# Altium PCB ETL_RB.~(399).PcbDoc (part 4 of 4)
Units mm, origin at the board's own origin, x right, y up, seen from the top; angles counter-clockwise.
Board outline 130.3 x 56.5 mm, 8 copper layers (Top Layer, plane 1, M1, plane 2, plane 3, M2, plane 4, Bottom Layer), stack 0.972 mm thick; 211 components, 188 nets, 1930 pads, 1008 vias.
Unrouted connection lines stored in the file: 383.

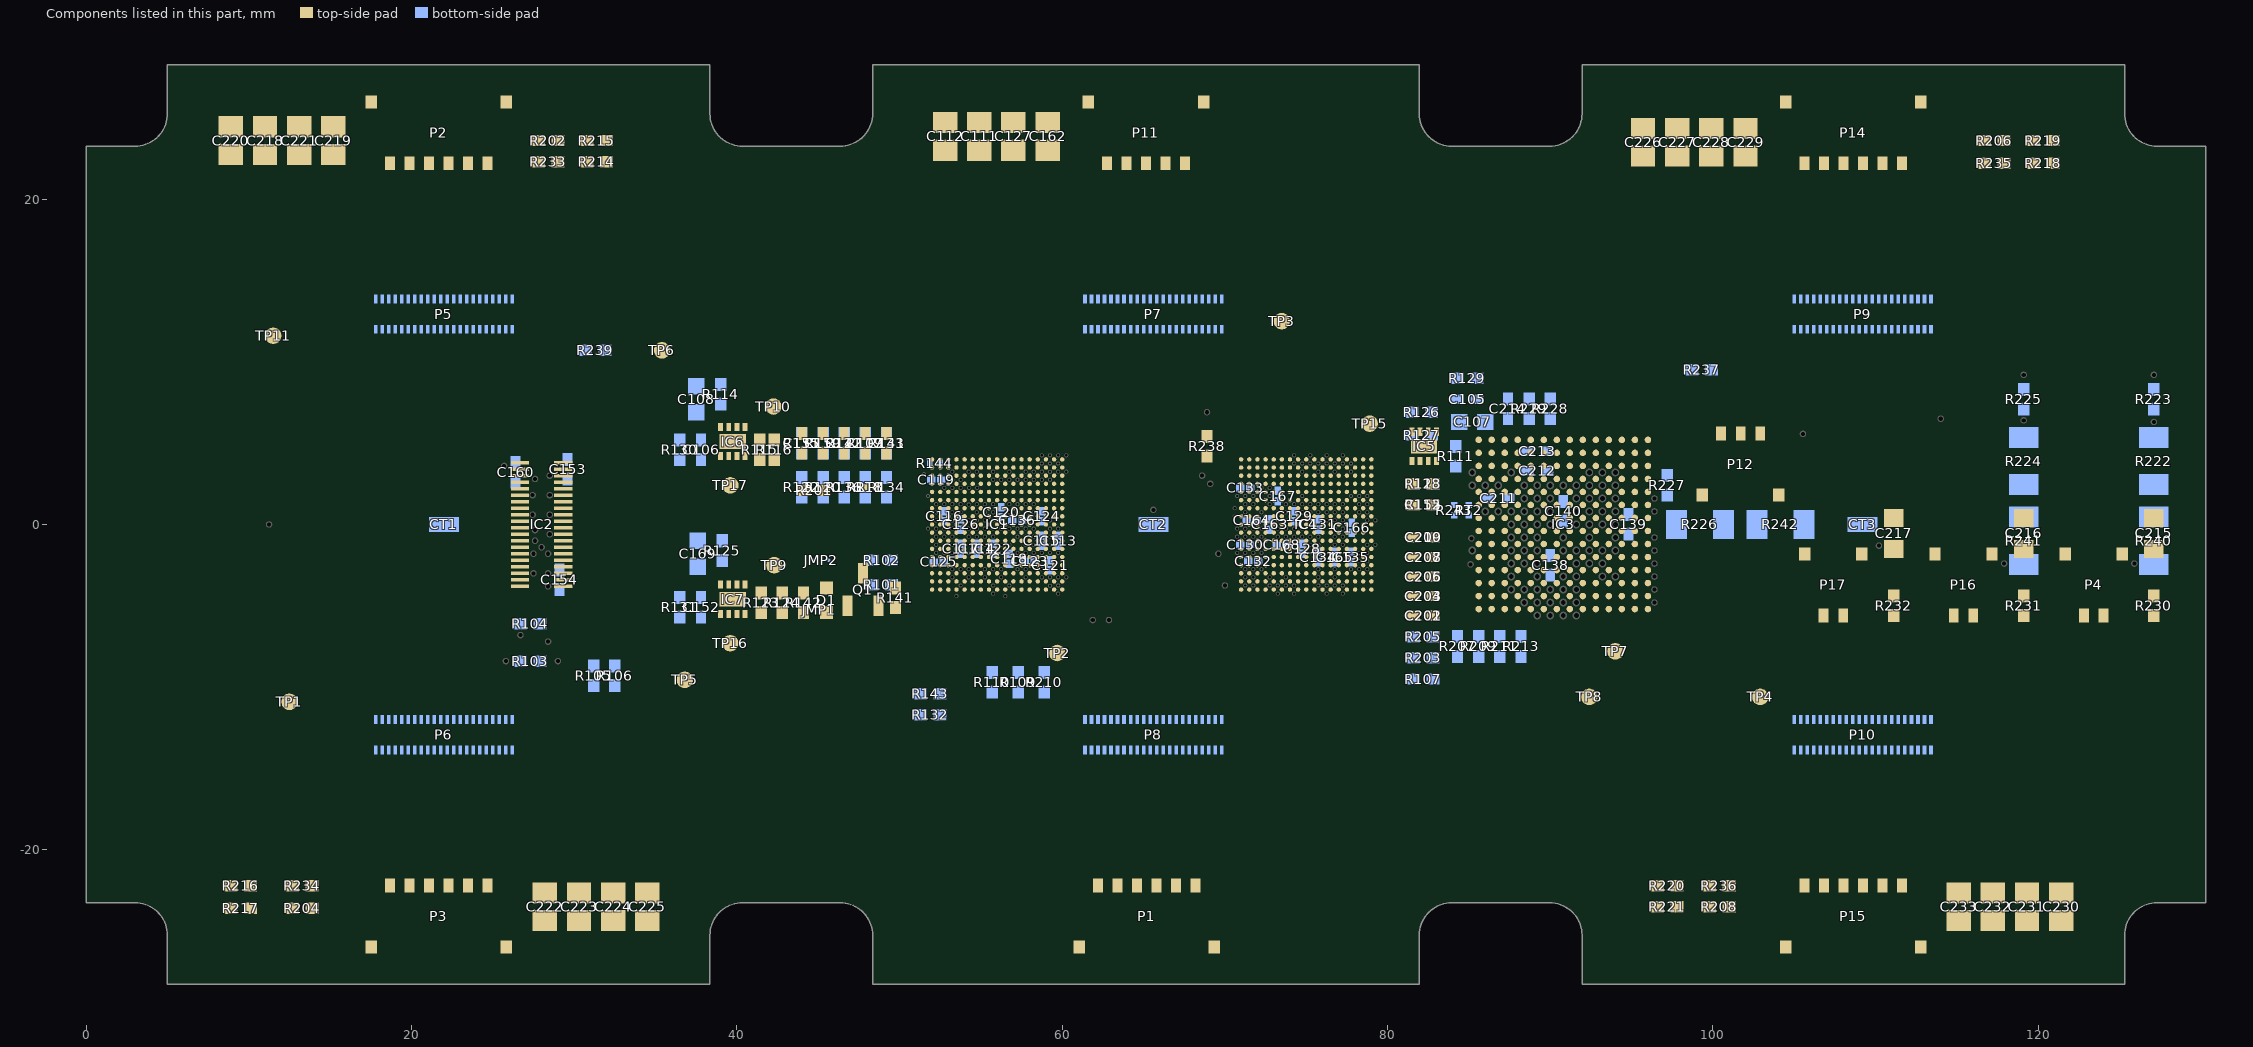
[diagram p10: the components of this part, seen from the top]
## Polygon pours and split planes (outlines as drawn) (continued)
1V2C on plane 3 (split plane): 124.79,25.25 124.79,25.249 124.799,25.031 124.828,24.814 124.875,24.6 124.941,24.391 125.025,24.189 125.126,23.995 125.244,23.81 125.377,23.636 125.525,23.475 125.686,23.327 125.86,23.194 126.045,23.076 126.239,22.975 126.441,22.891 126.65,22.825 126.864,22.778 127.081,22.749 127.299,22.74 127.3,22.74 129.79,22.74 129.79,7.078 111.278,7.078 111.278,11.522 112.5,11.522 112.53,11.528 112.555,11.545 114.055,13.045 114.072,13.07 114.078,13.1 114.078,16.1 114.072,16.13 114.055,16.155 114.03,16.172 114,16.178 81.5,16.178 81.47,16.172 81.445,16.155 74.068,8.778 65.678,8.778 65.678,11.768 66.332,12.422 69.2,12.422 69.23,12.428 69.255,12.445 70.855,14.045 70.872,14.07 70.878,14.1 70.878,27.74 81.44,27.74 81.44,25.25 81.44,25.249 81.449,25.031 81.478,24.814 81.525,24.6 81.591,24.391 81.675,24.189 81.776,23.995 81.894,23.81 82.027,23.636 82.175,23.475 82.336,23.327 82.51,23.194 82.695,23.076 82.889,22.975 83.091,22.891 83.3,22.825 83.514,22.778 83.731,22.749 83.949,22.74 83.95,22.74 89.95,22.74 89.951,22.74 90.169,22.749 90.386,22.778 90.6,22.825 90.809,22.891 91.011,22.975 91.205,23.076 91.39,23.194 91.564,23.327 91.725,23.475 91.873,23.636 92.006,23.81 92.124,23.995 92.225,24.189 92.309,24.391 92.375,24.6 92.422,24.814 92.451,25.031 92.46,25.249 92.46,25.25 92.46,27.74 124.79,27.74
GND on plane 4 (split plane): 271 vertices, not listed, extent 0.51,-27.74 129.79,27.74
GND on plane 1 (split plane): 271 vertices, not listed, extent 0.51,-27.74 129.79,27.74
GND on plane 2 (split plane): 113.972,15.868 113.972,9.282 112.818,8.128 102.532,8.128 98.905,11.755 98.88,11.772 98.85,11.778 82.05,11.778 82.02,11.772 81.995,11.755 76.668,6.428 64.1,6.428 64.07,6.422 64.045,6.405 59.968,2.328 55.532,2.328 55.055,2.805 55.03,2.822 55,2.828 54.282,2.828 45.255,11.855 45.23,11.872 45.2,11.878 31.3,11.878 31.27,11.872 31.245,11.855 27.518,8.128 18.828,8.128 18.828,11.368 22.155,14.695 22.172,14.72 22.178,14.75 22.178,15.668 23.732,17.222 112.618,17.222
GND on plane 2 (split plane): 81.945,-3.255 81.97,-3.272 82,-3.278 85.2,-3.278 85.23,-3.272 85.255,-3.255 85.632,-2.878 92.018,-2.878 101.945,-12.805 101.97,-12.822 102,-12.828 107.218,-12.828 109.672,-15.282 109.672,-22.172 101.282,-22.172 95.005,-15.895 94.98,-15.878 94.95,-15.872 94.929,-15.876 94.908,-15.872 78.432,-15.872 75.455,-12.895 75.43,-12.878 75.4,-12.872 66.55,-12.872 66.52,-12.878 66.495,-12.895 65.545,-13.845 65.528,-13.87 65.522,-13.9 65.522,-15.268 64.868,-15.922 17.282,-15.922 16.828,-15.468 16.828,-9.532 17.282,-9.078 42,-9.078 42.03,-9.072 42.055,-9.055 47.782,-3.328 51.25,-3.328 51.28,-3.322 51.305,-3.305 52.282,-2.328 73.75,-2.328 73.78,-2.322 73.805,-2.305 74.282,-1.828 77.25,-1.828 77.28,-1.822 77.305,-1.805 78.532,-0.578 79.268,-0.578
1V2_RB on plane 2 (split plane): 271 vertices, not listed, extent 0.51,-27.74 129.79,27.74

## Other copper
Top Layer:
  rectangle net GND: 14.4,-26.4 35.3,-24.4
  rectangle net 1V2B: 23.2,-22.6 35.3,-18.8
  rectangle net GND: 8.1,24.6 27.1,26.4
  rectangle net 1V2A: 8.1,19.8 20.2,22.6
  rectangle net GND: 94.9,24.7 114.4,26.4
  rectangle net 1V2C: 94.9,18.7 107.2,22.7
  rectangle net 1V2D: 110.1,-22.6 122.1,-19.1
  rectangle net GND: 113.8,-26.4 122.2,-23.7
  rectangle net GND: 97.6,1.4 99.7,3.3
  rectangle net BV2: 108.8,-2.8 111.7,-0.9
  rectangle: 113.3,-2.8 114.4,-0.9
  rectangle: 121.3,-2.9 122.5,-0.9
  rectangle net BV1: 116.8,-2.9 119.7,-0.9
  rectangle net BV0: 124.8,-2.9 127.7,-0.9
  rectangle: 103.7,-2.8 106,-0.9
  rectangle: 103.7,1.4 105.8,3.3
  rectangle net LV_RB: 67.25,21.75 70.5,22.6
  rectangle net GND: 58,-22.7 62.5,-18.9
  rectangle net GND: 37.95,-5.1 38.65,-3.9
  rectangle net GND: 38.6,-5.1 39.05,-4.15
  rectangle net GND: 38.1,4.6 39,5.6
  rectangle net GND: 16.3,-21.1 22.6,-17.8
  rectangle net GND: 20.8,-22.6 22.6,-20.6
  rectangle net GND: 101.7,-26.4 115.5,-24.5
  rectangle net GND: 103.1,-21.1 109.6,-18.4
  rectangle net GND: 107.7,-22.6 109.6,-21.1
  rectangle net GND: 107.7,17.9 114.5,21.2
  rectangle net GND: 107.7,21 109.5,22.6
  rectangle net GND: 58,-26.4 72.4,-24.5
  rectangle net GND: 80.2,4.35 81.6,5.25
  rectangle net GND: 22.4,18.8 26.6,20.6
  rectangle net GND: 20.8,18.8 22.6,22.6
  rectangle net GND: 66.4,18.5 70.5,21.2
  rectangle net GND: 64.9,18.5 66.6,22.6
  rectangle net GND: 52,24.2 70.4,26.5
  rectangle net 1V2_RB: 52,20.2 64.3,22.6
  text "1" at 128.746,-21.121 h1.52 r90
  text "'.Pcb_File_Name_No_Path'     '.Layer_Name'    '.Print_Date'    '.Print_Time'" at 49.754,-31.238 h1.52
M1:
  text "3" at 128.746,-17.746 h1.52 r90
  text "'.Pcb_File_Name_No_Path'    '.Layer_Name'    '.Print_Date'    '.Print_Time'" at 49.754,-31.292 h1.52
M2:
  text "6" at 128.746,-12.371 h1.52 r90
  text "'.Pcb_File_Name_No_Path'    '.Layer_Name'    '.Print_Date'    '.Print_Time'" at 49.754,-31.292 h1.52
Bottom Layer:
  rectangle net GND: 37.5,4.6 38.8,5.6
  rectangle net GND: 37.5,-5.1 38.7,-3.9
  rectangle net GND: 58.7,12.425 70.1,13.425
  rectangle net GND: 26.1,2.1 27.9,3.1
  rectangle net GND: 28.2,2.4 29.9,3.3
  rectangle net GND: 28.1,-3.3 29.4,-2.4
  rectangle net GND: 14.8,9.3 17.9,12.7
  rectangle net GND: 58.7,9.3 61.4,12.6
  rectangle net GND: 63.7,9.3 65.5,12.6
  rectangle net GND: 107.3,9.3 109.1,12.6
  rectangle net GND: 101.7,9.3 105.1,13.425
  rectangle net GND: 101.7,12.425 113.7,13.425
  rectangle net GND: 20.1,9.3 21.9,12.6
  rectangle net GND: 22.1,-12.6 23.9,-11.4
  rectangle net GND: 22.1,-11.5 24.7,-9.3
  rectangle net GND: 110.1,-12.6 111.1,-11.4
  rectangle net GND: 110.1,-11.5 111.9,-9.3
  rectangle net GND: 113.3,-12.7 116.7,-9.3
  rectangle net GND: 67.4,-11.5 68.3,-9.3
  rectangle net GND: 66.1,-12.6 67.5,-9.3
  rectangle net GND: 69.7,-12.7 73.1,-9.3
  rectangle net GND: 26.1,-12.7 29.5,-9.3
  region net GND: 29.5,-12.425 17.5,-12.425 17.5,-13.425 29.5,-13.425
  region net GND: 73.1,-12.425 61.1,-12.425 61.1,-13.425 73.1,-13.425
  region net GND: 116.7,-12.425 104.7,-12.425 104.7,-13.425 116.7,-13.425
  rectangle net GND: 14.8,12.4 26.3,13.4
  rectangle net 1V2_RB: 25.3,3.4 26.3,4.2
  rectangle net 2V5TX: 29.85,3.6 30.65,4.4
  rectangle net 2V5RX: 28.1,-4.4 28.9,-3.6
  rectangle net 1V2C: 67.7,9.275 69.5,12.275
  rectangle net 1V2C: 65.7,9.275 67.5,12.275
  rectangle net 1V2D: 109.3,9.275 111.1,12.275
  rectangle net 1V2C: 111.3,9.275 113.1,12.275
  region net 1V2D: 109.1,-9.275 107.3,-9.275 107.3,-12.275 109.1,-12.275
  region net 1V2D: 107.1,-9.275 105.3,-9.275 105.3,-12.275 107.1,-12.275
  region net 1V2B: 65.5,-9.275 63.7,-9.275 63.7,-12.275 65.5,-12.275
  region net 1V2B: 63.5,-9.275 61.7,-9.275 61.7,-12.275 63.5,-12.275
  region net 1V2B: 19.9,-9.275 18.1,-9.275 18.1,-12.275 19.9,-12.275
  region net 1V2A: 21.9,-9.275 20.1,-9.275 20.1,-12.275 21.9,-12.275
  rectangle net 1V2A: 22.1,9.275 23.9,12.275
  rectangle net 1V2A: 24.1,9.275 25.9,12.275
  text "8" at 128.746,-8.871 h1.52 r90
  text "'.Pcb_File_Name_No_Path'    '.Layer_Name'    '.Print_Date'    '.Print_Time'" at 49.754,-31.238 h1.52
plane 1 (plane layer: these items are gaps in the copper):
  rectangle: 12,-5 24.2,5
  rectangle: 126.75,-18.25 129.25,-7.5
  text "2" at 128.746,-19.621 h1.52 r90
  text "'.Pcb_File_Name_No_Path'    '.Layer_Name'    '.Print_Date'    '.Print_Time'" at 49.754,-31.238 h1.52
plane 2 (plane layer: these items are gaps in the copper):
  rectangle: 12,-5 24.2,5
  rectangle: 126.75,-20 129.25,-16.25
  rectangle: 126.75,-14.5 129.25,-7.5
  lines w0.152: 94.908,-15.95 78.4,-15.95 75.4,-12.95 66.55,-12.95 65.6,-13.9 65.6,-15.3 ; 94.95,-15.95 101.25,-22.25 109.75,-22.25 109.75,-15.25 107.25,-12.75 102,-12.75 92.05,-2.8 85.6,-2.8 85.2,-3.2 82,-3.2 79.3,-0.5 78.5,-0.5 77.25,-1.75 74.25,-1.75 73.75,-2.25 63.25,-2.25 52.25,-2.25 51.25,-3.25 47.75,-3.25 42,-9 17.25,-9 16.75,-9.5 16.75,-15.5 17.25,-16 64.9,-16 ; 64.9,-16 65.6,-15.3 ; 64.9,-16 65.6,-15.3 ; 18.75,8.05 18.75,11.4 22.1,14.75 22.1,15.7 23.7,17.3 112.65,17.3 114.05,15.9 114.05,9.25 112.85,8.05 102.5,8.05 98.85,11.7 82.05,11.7 76.7,6.35 64.1,6.35 60,2.25 55.5,2.25 55,2.75 54.25,2.75 45.2,11.8 31.3,11.8 27.55,8.05 18.75,8.05
  text "4" at 128.746,-15.871 h1.52 r90
  text "'.Pcb_File_Name_No_Path'    '.Layer_Name'    '.Print_Date'    '.Print_Time'" at 49.754,-31.238 h1.52
plane 3 (plane layer: these items are gaps in the copper):
  rectangle: 126.75,-20 129.25,-14.5
  rectangle: 126.75,-12.75 129.25,-7.5
  lines w0.152: 0,-8 20,-8 20,-11.5 ; 28.5,28.2 28.5,28.3 ; 29,28.2 29,28.3 29,17 18.5,17 18.5,12 29,12 29,6 25,6 25,-11.5 20,-11.5 ; 70.8,28.3 70.8,14.1 69.2,12.5 ; 75,-28 75,-8.5 60.5,-8.5 60.5,-10.5 62.1,-12.1 68.8,-12.1 68.8,-16.5 17.5,-16.5 17.5,-14 20,-11.5 ; 95.1,-28.3 95.1,-15.8 112.5,-15.8 112.5,-11.5 101.7,-11.5 101.7,11.6 111.2,11.6 ; 130.3,7 130.3,7.1 130.2,7 111.2,7 111.2,11.6 ; 69.2,12.5 69.2,12.5 ; 69.2,12.5 66.3,12.5 65.6,11.8 65.6,8.7 74.1,8.7 81.5,16.1 114,16.1 114,13.1 112.5,11.6 111.2,11.6 ; 79.9,-2.8 85.6,-8.5 95.5,-8.5 95.5,10 83,10 79.9,6.9 79.9,-2.8 ; 82.5,4.1 83.8,2.8 89.6,2.8 89.6,-4.4 92,-4.4 92,5.6 82.5,5.6 82.5,4.1
  text "5" at 128.746,-14.121 h1.52 r90
  text "'.Pcb_File_Name_No_Path'    '.Layer_Name'     '.Print_Date'     '.Print_Time'" at 49.754,-31.238 h1.52
plane 4 (plane layer: these items are gaps in the copper):
  rectangle: 126.75,-9.25 129.25,-7.5
  rectangle: 126.75,-20 129.25,-12.75
  text "7" at 128.746,-10.621 h1.52 r90
  text "'.Pcb_File_Name_No_Path'    '.Layer_Name'    '.Print_Date'    '.Print_Time'" at 49.754,-31.238 h1.52

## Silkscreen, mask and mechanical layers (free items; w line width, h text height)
Top Overlay:
  lines w0.102: 12.15,-4.75 24,-4.75 24,4.75 12.15,4.75 12.15,-4.75
  text "09_09_2020" at 8.892,-6.946 h1.52 r90
  text "ETL_RB_v1.1" at 5.561,-10.2 h2.03 r90
  text "'.Pcb_File_Name_No_Path'    '.Layer_Name'    '.Print_Date'    '.Print_Time'" at 49.654,-31.238 h1.52
Bottom Overlay:
  text "ETL_RB_v1.1" at 5.061,10.1 h2.03 r90
  text "09_09_2020" at 8.292,6.946 h1.52 r90
  text "'.Pcb_File_Name_No_Path'    '.Layer_Name'    '.Print_Date'    '.Print_Time'" at 49.654,-31.438 h1.52
Top Paste:
  text "'.Pcb_File_Name_No_Path'    '.Layer_Name'    '.Print_Date'    '.Print_Time'" at 49.554,-31.338 h1.52
Bottom Paste:
  text "'.Pcb_File_Name_No_Path'    '.Layer_Name'    '.Print_Date'    '.Print_Time'" at 49.554,-31.592 h1.52
Top Solder:
  text "'.Pcb_File_Name_No_Path'    '.Layer_Name'    '.Print_Date'    '.Print_Time'" at 49.554,-31.338 h1.52
Bottom Solder:
  text "'.Pcb_File_Name_No_Path'    '.Layer_Name'    '.Print_Date'    '.Print_Time'" at 49.554,-31.592 h1.52
Drill Guide:
  text "'.Pcb_File_Name_No_Path'    '.Layer_Name'    '.Print_Date'    '.Print_Time'" at 49.554,-31.592 h1.52
Mechanical 1:
  the board outline again, w0.15
Mechanical 14:
  the board outline again, w0.15
  text "12X" at -17.346,-27.946 h1.52
  text "'.Pcb_File_Name_No_Path'    '.Layer_Name'    '.Print_Date'    '.Print_Time'" at 49.754,-31.192 h1.52
  text "We adopted the layer stack recommended by you. The stack file is included in the manufacturing documentation." at -6.446,-35.338 h1.52
  text "The surfatce treatment of top and bottom layers is immersion gold." at -6.746,-37.938 h1.52
  text "We have high voltage up to 1000V on some components, so please chose the solder mask material with this in mind." at -6.546,-41.238 h1.52
  text "Traces with 0.12mm width are impedance controlled signals. Please tune the width to get to 50 Ohm." at -6.746,-44.238 h1.52
Drill Drawing:
  text "'.Pcb_File_Name_No_Path'    '.Layer_Name'    '.Print_Date'    '.Print_Time'" at 49.754,-31.238 h1.52

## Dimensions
137.8,-28.25 to 125.3,28.25 on Mechanical 14
132.3,-28.25 to 130.3,23.25 on Mechanical 14
125.3,-28.25 to 130.3,-23.25 on Mechanical 14
4.6,-24 to 1.3,-27 on Mechanical 14
0,44.1 to 130.3,23.25 on Mechanical 14
0,40.8 to 125.3,28.25 on Mechanical 14
0,37.4 to 91.95,28.25 on Mechanical 14
0,35.3 to 81.95,28.25 on Mechanical 14
0,32.7 to 48.35,28.25 on Mechanical 14
0,30.028 to 38.35,28.24 on Mechanical 14
0,23.25 to 5,28.25 on Mechanical 14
